VERSION 5.7 ;
BUSBITCHARS "[]" ;
DIVIDERCHAR "/" ;

PROPERTYDEFINITIONS
  MACRO CatenaDesignType STRING ;
  LAYER LEF58_TYPE STRING ;
  LAYER LEF58_ENCLOSURE STRING ;
  LAYER LEF58_SPACING STRING ;
  LAYER LEF58_WIDTH STRING ;
END PROPERTYDEFINITIONS

UNITS
  DATABASE MICRONS 1000 ;
END UNITS
MANUFACTURINGGRID 0.01 ;
LAYER OVERLAP
  TYPE OVERLAP ;
END OVERLAP

LAYER NWELL
  TYPE MASTERSLICE ;
  PROPERTY LEF58_TYPE "TYPE NWELL ;" ;
  PROPERTY LEF58_SPACING "SPACING 1.25 ;" ;
  PROPERTY LEF58_WIDTH "WIDTH 2.5 ;" ;
END NWELL

LAYER ACT
  TYPE MASTERSLICE ;
  PROPERTY LEF58_TYPE "TYPE DIFFUSION ;" ;
  PROPERTY LEF58_SPACING "SPACING 1 ;" ;
  PROPERTY LEF58_WIDTH "WIDTH 0.7 ;" ;
END ACT

LAYER POLY1
  TYPE MASTERSLICE ;
END POLY1

LAYER POLY2
  TYPE MASTERSLICE ;
END POLY2

LAYER NSD
  TYPE IMPLANT ;
  WIDTH 0.75 ;
  SPACING 0.75 ;
END NSD

LAYER PSD
  TYPE IMPLANT ;
  WIDTH 0.75 ;
  SPACING 0.75 ;
END PSD

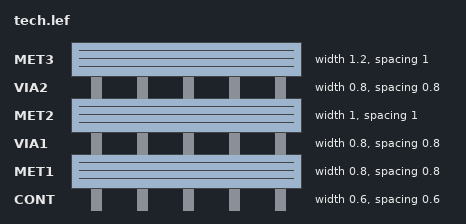
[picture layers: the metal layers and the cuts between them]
LAYER CONT
  TYPE CUT ;
  SPACING 0.6 ;
  WIDTH 0.6 ;
END CONT

LAYER MET1
  TYPE ROUTING ;
  DIRECTION HORIZONTAL ;
  WIDTH 0.8 ;
  SPACING 0.8 ;
  SPACING 0.8 SAMENET ;
END MET1

LAYER VIA1
  TYPE CUT ;
  SPACING 0.8 ;
  WIDTH 0.8 ;
END VIA1

LAYER MET2
  TYPE ROUTING ;
  DIRECTION HORIZONTAL ;
  WIDTH 1 ;
  SPACING 1 ;
  SPACING 1 SAMENET ;
END MET2

LAYER VIA2
  TYPE CUT ;
  SPACING 0.8 ;
  WIDTH 0.8 ;
END VIA2

LAYER MET3
  TYPE ROUTING ;
  DIRECTION HORIZONTAL ;
  WIDTH 1.2 ;
  SPACING 1 ;
  SPACING 1 SAMENET ;
END MET3

VIARULE M3_M2 GENERATE
  LAYER MET2 ;
    ENCLOSURE 0.6 0.6 ;
  LAYER MET3 ;
    ENCLOSURE 0.6 0.6 ;
  LAYER VIA2 ;
    RECT -0.4 -0.4 0.4 0.4 ;
    SPACING 1.6 BY 1.6 ;
END M3_M2

VIARULE M2_M1 GENERATE
  LAYER MET1 ;
    ENCLOSURE 0.6 0.6 ;
  LAYER MET2 ;
    ENCLOSURE 0.6 0.6 ;
  LAYER VIA1 ;
    RECT -0.4 -0.4 0.4 0.4 ;
    SPACING 1.6 BY 1.6 ;
END M2_M1

VIARULE M1_POLY1 GENERATE
  LAYER POLY1 ;
    ENCLOSURE 0.5 0.5 ;
  LAYER MET1 ;
    ENCLOSURE 0.6 0.6 ;
  LAYER CONT ;
    RECT -0.3 -0.3 0.3 0.3 ;
    SPACING 1.2 BY 1.2 ;
END M1_POLY1

VIARULE M1_POLY2 GENERATE
  LAYER POLY2 ;
    ENCLOSURE 0.5 0.5 ;
  LAYER MET1 ;
    ENCLOSURE 0.6 0.6 ;
  LAYER CONT ;
    RECT -0.3 -0.3 0.3 0.3 ;
    SPACING 1.2 BY 1.2 ;
END M1_POLY2

VIARULE M1_NACT GENERATE
  LAYER ACT ;
    ENCLOSURE 0.5 0.5 ;
  LAYER MET1 ;
    ENCLOSURE 0.6 0.6 ;
  LAYER CONT ;
    RECT -0.3 -0.3 0.3 0.3 ;
    SPACING 1.2 BY 1.2 ;
END M1_NACT

VIARULE M1_PACT GENERATE
  LAYER ACT ;
    ENCLOSURE 0.5 0.5 ;
  LAYER MET1 ;
    ENCLOSURE 0.6 0.6 ;
  LAYER CONT ;
    RECT -0.3 -0.3 0.3 0.3 ;
    SPACING 1.2 BY 1.2 ;
END M1_PACT

VIARULE M1_NWELL GENERATE
  LAYER ACT ;
    ENCLOSURE 0.5 0.5 ;
  LAYER MET1 ;
    ENCLOSURE 0.6 0.6 ;
  LAYER CONT ;
    RECT -0.3 -0.3 0.3 0.3 ;
    SPACING 1.2 BY 1.2 ;
END M1_NWELL

END LIBRARY
